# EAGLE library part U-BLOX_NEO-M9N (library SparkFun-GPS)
u-blox NEO-M9N GPS Module The NEO-M9N module is built on the robust u-blox M9 GNSS chip, which provides exceptional sensitivity and acquisition times for all L1 GNSS systems. The u-blox M9 standard precision GNSS platform, which delivers meter-level accuracy, succeeds the well-known u-blox M8 product range. The receiver also provides higher navigation rate and improved security features compared to previous u-blox GNSS generations. The NEO-M9N module is available in the NEO form factor LLC package

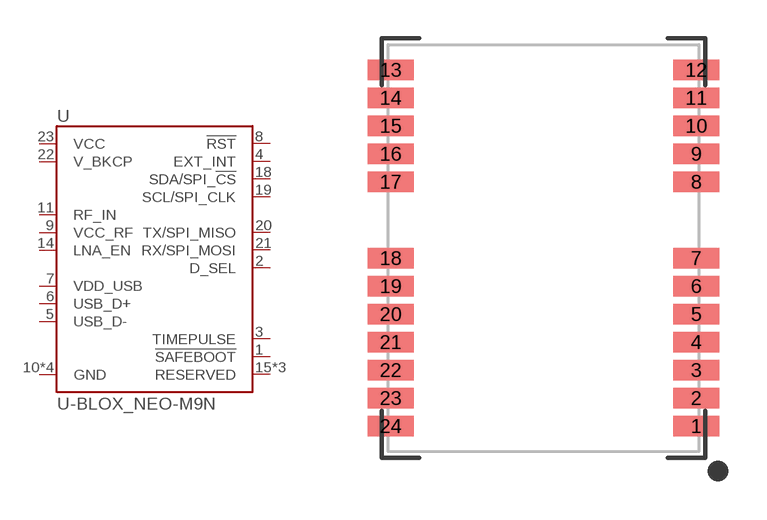
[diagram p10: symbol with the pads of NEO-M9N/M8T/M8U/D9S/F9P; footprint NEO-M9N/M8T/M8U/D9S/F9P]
Designator prefix U

## U-BLOX_NEO-M9N (PROD_ID: IC-14651)  [NEO-M9N/M8T/M8U/D9S/F9P]
1  !SAFEBOOT!
2  D_SEL
3  TIMEPULSE
4  EXT_INT
5  USB_D-
6  USB_D+
7  VDD_USB
8  !RST
9  VCC_RF
10  GND
11  RF_IN
12  GND
13  GND
14  LNA_EN
15  RESERVED  nc
16  RESERVED  nc
17  RESERVED  nc
18  SDA/SPI_!CS!
19  SCL/SPI_CLK
20  TX/SPI_MISO
21  RX/SPI_MOSI
22  V_BKCP
23  VCC
24  GND

## Footprint NEO-M9N/M8T/M8U/D9S/F9P (pad centres in mm)
u-blox NEO-M9N/M8T/M8U/D9S Module Mechanical Specifications Overall: 12.2mm x 16.0mm Pad Pitch: 1.1mm Pad Width: .8mm Pad Length: .9mm Number of Pins: 24
smd 1.8 x 0.8: 1 6,-7; 2 6,-5.9; 3 6,-4.8; 4 6,-3.7; 5 6,-2.6; 6 6,-1.5; 7 6,-0.4; 8 6,2.6; 9 6,3.7; 10 6,4.8; 11 6,5.9; 12 6,7; 13 -6,7; 14 -6,5.9; 15 -6,4.8; 16 -6,3.7; 17 -6,2.6; 18 -6,-0.4; 19 -6,-1.5; 20 -6,-2.6; 21 -6,-3.7; 22 -6,-4.8; 23 -6,-5.9; 24 -6,-7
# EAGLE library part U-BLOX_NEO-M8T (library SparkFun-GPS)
u-blox NEO-M8T The NEO-M8T and LEA-M8T concurrent GNSS modules deliver high integrity, precision timing in demanding applicationsworld-wide. Support for BeiDou, GLONASS and Galileo constellations enables compliance with national requirements. Enhanced sensitivity and concurrent constellation reception extend coverage and integrity to challenging signal environments. Survey-in and fixed-position navigation reduce timing jitter, even at low signal levels, and enable synchronization to be maintained with as few as one single satellite in view. Support for low duty cycle operation reduces power consumption for battery-powered applications. u-blox timing products include timing integrity measures with Receiver Autonomous Integrity Monitoring (RAIM) and continuous phase uncertainty estimation. They feature high dynamic range radios with both analog and digital interference mitigation, supporting applications in wireless communications equipment. The M8T timing modules are delivered in u-blox’s established LEA and NEO form-factors with standard pin-out, allowing ready migration from previous product generations. u-blox timing products can make use of u-blox AssistNow or industry-standard aiding data. This reduces the time-to-firstfix and delivers exceptional acquisition sensitivity, even on first installation before precise location, time or frequency are known.

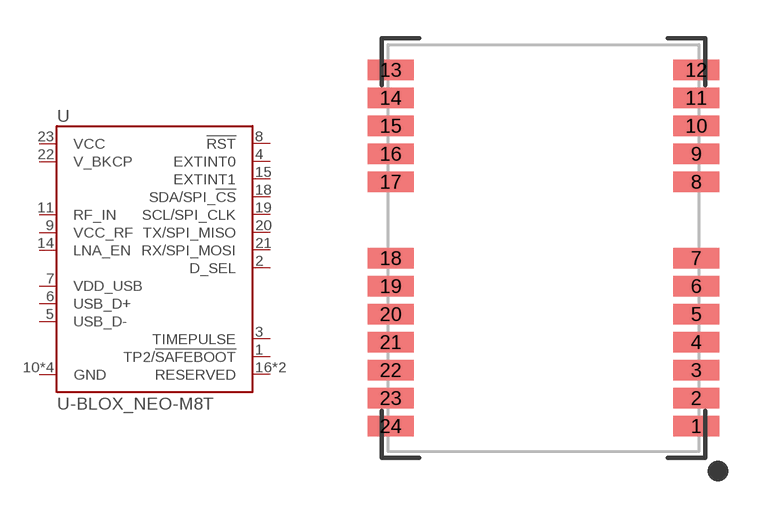
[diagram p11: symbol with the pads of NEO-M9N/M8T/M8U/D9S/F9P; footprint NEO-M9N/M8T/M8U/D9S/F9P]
Designator prefix -

## U-BLOX_NEO-M8T (PROD_ID: IC-14839)  [NEO-M9N/M8T/M8U/D9S/F9P]
1  TP2/!SAFEBOOT!
2  D_SEL
3  TIMEPULSE
4  EXTINT0
5  USB_D-
6  USB_D+
7  VDD_USB
8  !RST
9  VCC_RF
10  GND
11  RF_IN
12  GND
13  GND
14  LNA_EN
15  EXTINT1
16  RESERVED  nc
17  RESERVED  nc
18  SDA/SPI_!CS!
19  SCL/SPI_CLK
20  TX/SPI_MISO
21  RX/SPI_MOSI
22  V_BKCP
23  VCC
24  GND

## Footprint NEO-M9N/M8T/M8U/D9S/F9P (pad centres in mm)
u-blox NEO-M9N/M8T/M8U/D9S Module Mechanical Specifications Overall: 12.2mm x 16.0mm Pad Pitch: 1.1mm Pad Width: .8mm Pad Length: .9mm Number of Pins: 24
smd 1.8 x 0.8: 1 6,-7; 2 6,-5.9; 3 6,-4.8; 4 6,-3.7; 5 6,-2.6; 6 6,-1.5; 7 6,-0.4; 8 6,2.6; 9 6,3.7; 10 6,4.8; 11 6,5.9; 12 6,7; 13 -6,7; 14 -6,5.9; 15 -6,4.8; 16 -6,3.7; 17 -6,2.6; 18 -6,-0.4; 19 -6,-1.5; 20 -6,-2.6; 21 -6,-3.7; 22 -6,-4.8; 23 -6,-5.9; 24 -6,-7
